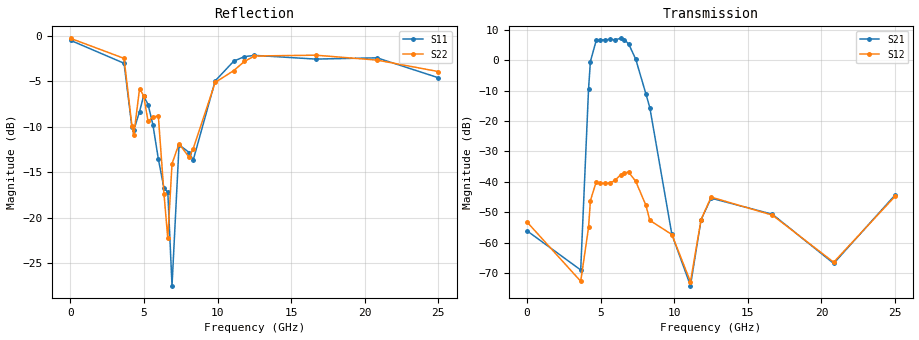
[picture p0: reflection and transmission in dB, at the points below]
!Agilent Technologies,E8364B,MY43040894,A.07.50.67
!Agilent E8364B: A.07.50.67
!Date: Wednesday, July 07, 2021 13:19:57
!Correction: S11(Full 2 Port(1,2))
!S21(Full 2 Port(1,2))
!S12(Full 2 Port(1,2))
!S22(Full 2 Port(1,2))
!S2P File: Measurements: S11, S21, S12, S22:
# Hz S  dB  R 50
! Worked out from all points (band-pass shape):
!   8001 points, 10 MHz to 25 GHz, reference 50 ohm
!   highest |S21| = 7.17 dB at 6.361 GHz (marker M1); lowest = -74.1 dB at 11.1 GHz (marker M2)
!   |S21| within 3 dB of the highest: 4.449 GHz to 7.06 GHz (2.611 GHz wide, 45.4 % of centre)
!   lowest |S11| = -27.5 dB at 6.904 GHz (marker M3), VSWR 1.09, Z = 46 - j0.422 ohm
!   |S11| at or under -10 dB: 4.179 GHz to 4.331 GHz (151.5 MHz wide, 3.56 % of centre); 5.634 GHz to 8.825 GHz (3.192 GHz wide, 44.1 % of centre)
!   |S22| runs from -23.4 to -0.3 dB; largest |S21 - S12| = 2.3
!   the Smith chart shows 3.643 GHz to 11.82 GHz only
!   S11 on the Smith chart (normalised r, x): 3.643 GHz: 0.48, -1.30; 4.302 GHz: 0.68, -0.41; 6.617 GHz: 0.77, +0.10; 8.072 GHz: 1.10, +0.48; 9.837 GHz: 0.49, -0.81; 11.82 GHz: 0.13, -0.06
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1e7  -0.48 -5.5  -56.12 -7.7  -53.26 28.0  -0.26 -6.0
3.642921e9  -3.00 -70.5  -68.94 -140.5  -72.64 -145.8  -2.46 -69.5
4.177082e9  -9.96 -128.9  -9.42 -172.5  -54.95 35.5  -9.85 -134.2
4.302032e9  -10.39 -113.9  -0.44 109.2  -46.13 -42.3  -10.94 -112.5
4.698749e9  -8.31 -124.8  6.51 -93.2  -40.00 130.3  -5.78 -133.9
4.973639e9  -6.59 -142.6  6.51 170.2  -40.46 46.3  -6.58 -158.0
5.276642e9  -7.54 -169.2  6.73 84.0  -40.49 -27.8  -9.40 -170.9
5.604636e9  -9.76 172.3  6.82 -5.8  -40.37 -102.7  -8.91 -170.5
5.973239e9  -13.52 155.9  6.73 -99.8  -39.53 178.7  -8.78 156.0
6.360584e9  -16.77 169.1  7.17 156.6  -37.62 87.2  -17.42 118.4
6.616731e9  -17.15 153.1  6.74 81.8  -36.96 19.0  -22.27 -173.2
6.904116e9  -27.47 -173.8  5.31 -4.0  -36.85 -61.5  -14.05 -168.6
7.38205e9  -11.97 -174.5  0.34 -152.5  -39.79 153.8  -11.85 134.2
8.072399e9  -12.82 64.8  -11.03 6.1  -47.65 -30.8  -13.35 57.3
8.341041e9  -13.67 24.3  -15.62 -84.8  -52.63 -102.6  -12.41 18.7
9.837318e9  -4.94 -93.7  -57.21 169.2  -57.29 168.5  -5.11 -112.0
1.110244e10  -2.76 -148.0  -74.10 -3.8  -72.81 0.1  -3.80 -159.2
1.182402e10  -2.27 -173.3  -52.37 -161.5  -52.38 -161.2  -2.80 176.9
1.2505e10  -2.13 163.8  -45.34 127.9  -44.99 129.6  -2.20 152.5
1.667208e10  -2.54 29.2  -50.63 -70.9  -50.91 -73.8  -2.11 13.3
2.083604e10  -2.40 -65.2  -66.79 102.3  -66.39 -115.6  -2.65 -78.0
2.5e10  -4.59 -123.0  -44.35 -95.3  -44.78 -93.4  -3.91 -133.8
